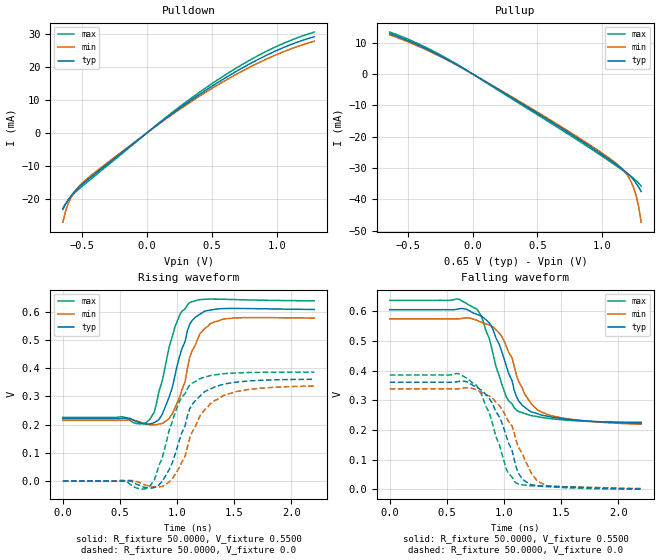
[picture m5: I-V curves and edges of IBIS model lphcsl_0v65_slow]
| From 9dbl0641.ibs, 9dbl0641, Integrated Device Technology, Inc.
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[Model]   lphcsl_0v65_slow
Model_type Output
Polarity   Non-Inverting
Enable   Active-High
Vmeas =  0.4000V
Cref =   2.0000pF
Rref =   0.0
Vref =   0.4000V
C_comp   1.1000pF   1.0000pF   1.2000pF
[Temperature Range]   25.0000   85.0000   -40.0000
[Voltage Range]   0.6500V   0.6200V   0.6800V
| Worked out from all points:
|   slope of the pulldown table from 0 to 0.098 V, typ, clamps not added: 32.8 ohm
|   slope of the pullup table from 0 to 0.098 V, typ, clamps not added: 40 ohm
|   rising waveform, R_fixture 50.0000, V_fixture 0.5500: 20-80 % time 158ps typ, 170ps min, 154ps max; typ from 0.221 V to 0.607 V
|   rising waveform, R_fixture 50.0000, V_fixture 0.0: 20-80 % time 204ps typ, 240ps min, 203ps max; typ from 0 V to 0.36 V
|   falling waveform, R_fixture 50.0000, V_fixture 0.5500: 20-80 % time 214ps typ, 239ps min, 199ps max; typ from 0.606 V to 0.223 V
|   falling waveform, R_fixture 50.0000, V_fixture 0.0: 20-80 % time 211ps typ, 241ps min, 199ps max; typ from 0.361 V to 0.001 V
[Pulldown]
|Voltage   I(typ)   I(min)   I(max)
-650mV    -23.23mA   -27.08mA   -22.85mA
-630mV    -21.73mA   -23.92mA   -21.53mA
-610mV    -20.42mA   -21.63mA   -20.41mA
-590mV    -19.28mA   -19.88mA   -19.45mA
-550mV    -17.42mA   -17.37mA   -17.87mA
-510mV    -15.92mA   -15.58mA   -16.5mA
-350mV    -10.82mA   -10.4mA    -11.34mA
130mV     3.938mA    3.75mA     4.173mA
450mV     12.8mA     12.19mA    13.51mA
770mV     20.38mA    19.39mA    21.48mA
1.03V     25.42mA    24.16mA    26.67mA
1.29V     29.08mA    27.71mA    30.47mA
[Pullup]
|Voltage   I(typ)   I(min)   I(max)
-640mV    12.9mA     12.48mA    13.37mA
-340mV    7.668mA    7.369mA    8.057mA
-40mV     988uA      943.5uA    1.052mA
700mV     -17.66mA   -17.23mA   -18.19mA
1.08V     -28.05mA   -27.62mA   -28.49mA
1.16V     -30.49mA   -30.54mA   -30.78mA
1.2V      -31.91mA   -32.71mA   -31.96mA
1.22V     -32.74mA   -34.19mA   -32.58mA
1.24V     -33.69mA   -36.08mA   -33.24mA
1.26V     -34.78mA   -38.62mA   -33.96mA
1.28V     -36.03mA   -42.17mA   -34.78mA
1.3V      -37.46mA   -47.25mA   -35.74mA
[Ramp]
| variable   typ   min   max
dV/dt_r  0.2161/0.2242n   0.2018/0.2534n   0.2312/0.1998n
dV/dt_f  0.2311/0.2438n   0.2145/0.2731n   0.2483/0.2072n
R_load = 50.0000
[Rising Waveform]
R_fixture= 50.0000
V_fixture= 0.5500
V_fixture_min= 0.5200
V_fixture_max= 0.5800
|time   V(typ)   V(min)   V(max)
0s        221mV      214.9mV    225.3mV
760ps     202.3mV    199.7mV    217.4mV
800ps     207mV      199.2mV    244.2mV
870ps     236.6mV    203.8mV    355.1mV
960ps     334.6mV    240.3mV    514.3mV
1.07ns    494.6mV    352mV      609.6mV
1.11ns    554.8mV    438.4mV    631.3mV
1.2ns     590.6mV    521.6mV    641.9mV
1.4ns     610.2mV    573mV      643.4mV
2.2ns     607.2mV    576.7mV    637.9mV
[Rising Waveform]
R_fixture= 50.0000
V_fixture= 0.0
V_fixture_min= 0.0
V_fixture_max= 0.0
|time   V(typ)   V(min)   V(max)
0s        0V         0V         0V
530ps     1.461mV    194.3uV    1.992mV
730ps     -23.41mV   -15.09mV   -26.03mV
800ps     -22.54mV   -20.61mV   3.759mV
960ps     66.54mV    9.62mV     212.7mV
1.07ns    195.9mV    88.33mV    309.7mV
1.13ns    270.3mV    172.7mV    346.1mV
1.24ns    316.7mV    252.3mV    368mV
1.4ns     341.7mV    301.9mV    379.7mV
2.2ns     360.2mV    336.4mV    385.4mV
[Falling Waveform]
R_fixture= 50.0000
V_fixture= 0.5500
V_fixture_min= 0.5200
V_fixture_max= 0.5800
|time   V(typ)   V(min)   V(max)
0s        605.5mV    574.4mV    637mV
600ps     607.9mV    574.5mV    641.2mV
760ps     590.4mV    570.4mV    608.8mV
890ps     550.3mV    550.2mV    479.5mV
980ps     464.9mV    515.1mV    355mV
1.07ns    366.1mV    443.3mV    288.1mV
1.13ns    297.2mV    362.1mV    261.8mV
1.24ns    260.4mV    287.7mV    248.2mV
1.38ns    246.3mV    251.9mV    239.7mV
2.2ns     223.2mV    219.5mV    225.9mV
[Falling Waveform]
R_fixture= 50.0000
V_fixture= 0.0
V_fixture_min= 0.0
V_fixture_max= 0.0
|time   V(typ)   V(min)   V(max)
0s        361mV      338.8mV    385.4mV
600ps     363.4mV    338.9mV    390.1mV
760ps     344.7mV    335.3mV    350.3mV
870ps     307.2mV    315mV      258.9mV
960ps     243.4mV    282.2mV    149mV
1.02ns    179.3mV    243.1mV    67.53mV
1.11ns    70.61mV    159.4mV    20.73mV
1.24ns    14.75mV    53.96mV    11.99mV
1.38ns    10.3mV     11.97mV    8.861mV
2.2ns     1.433mV    2.621mV    465.3uV
